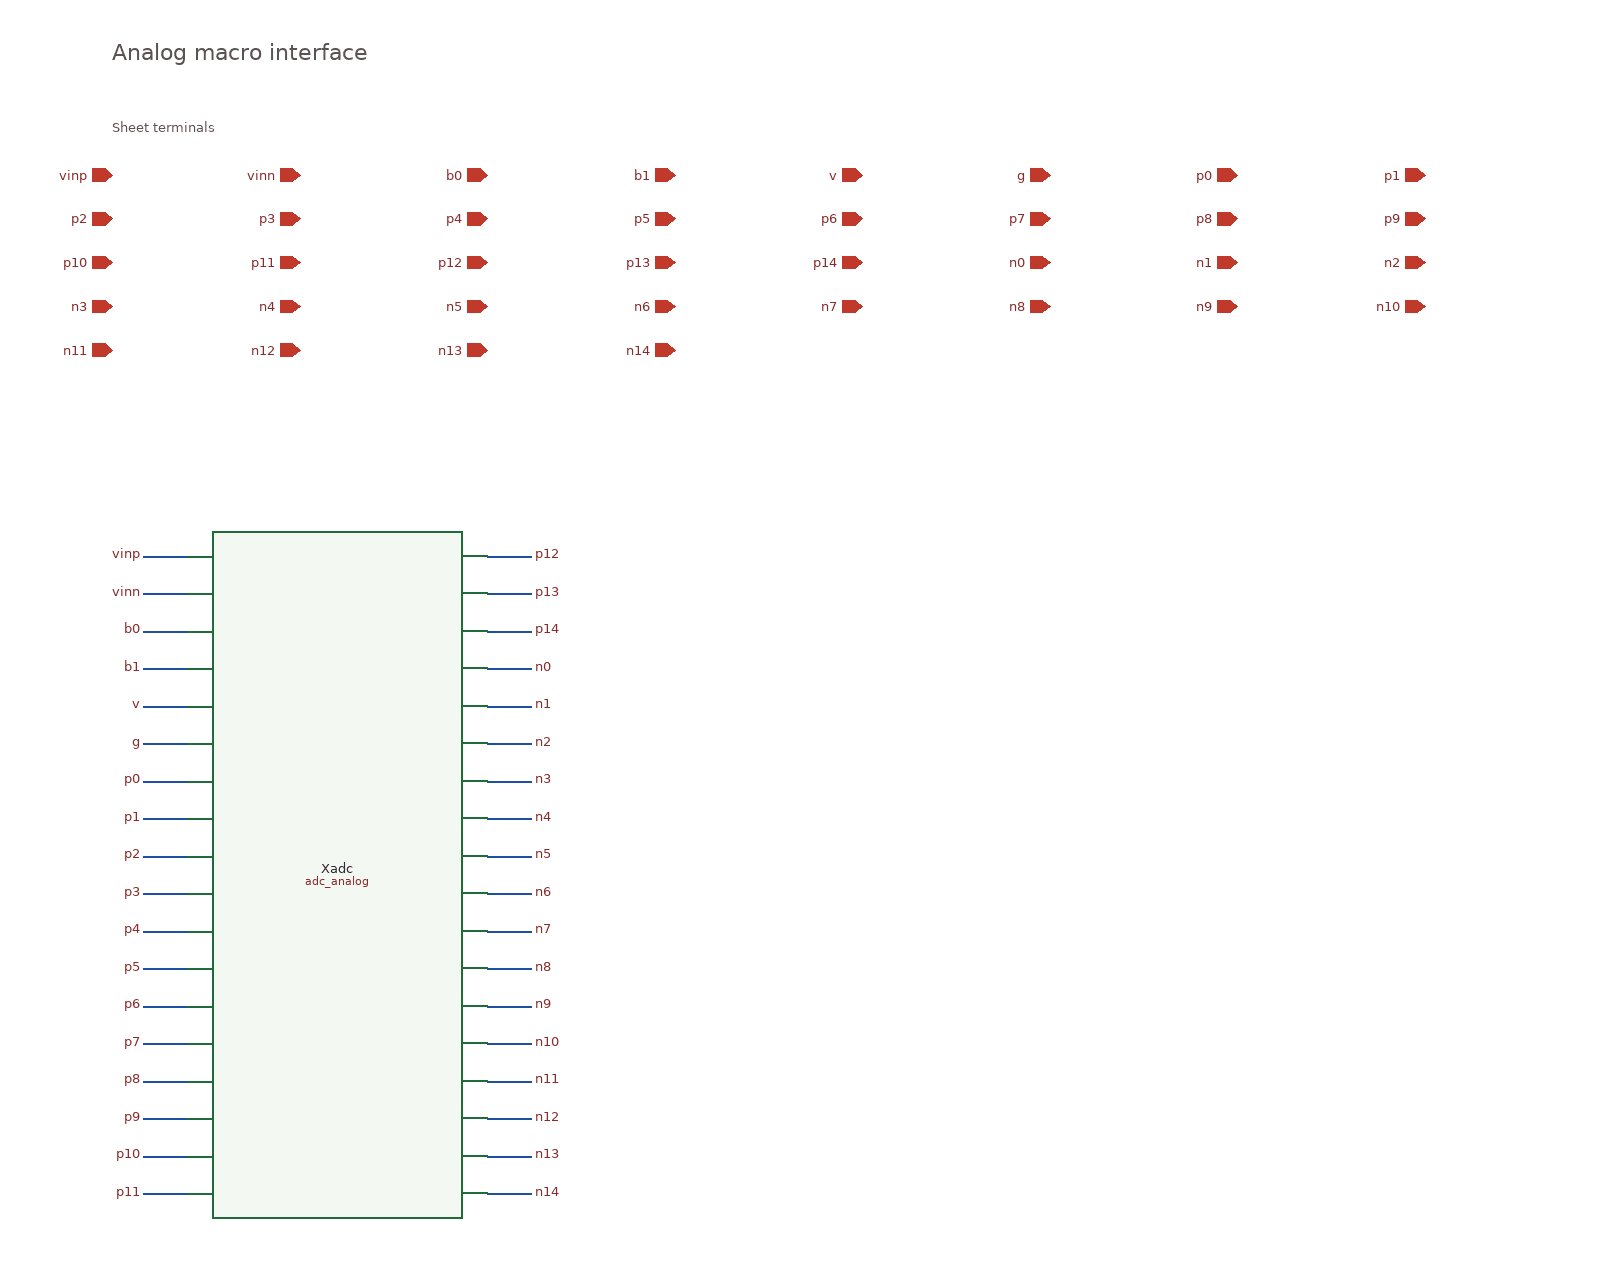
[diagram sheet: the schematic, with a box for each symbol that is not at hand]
v {xschem version=3.4.4 file_version=1.2}
G {}
K {}
V {}
S {}
E {}
T {Analog macro interface} 0 0 0 0 0.62 0.62 {}
T {Sheet terminals} 0 60 0 0 0.32 0.32 {layer=13}
C {devices/iopin.sym} 0 110 0 0 {name=io0 lab=vinp sim_pinnumber=1}
C {devices/iopin.sym} 150 110 0 0 {name=io1 lab=vinn sim_pinnumber=2}
C {devices/iopin.sym} 300 110 0 0 {name=io2 lab=b0 sim_pinnumber=3}
C {devices/iopin.sym} 450 110 0 0 {name=io3 lab=b1 sim_pinnumber=4}
C {devices/iopin.sym} 600 110 0 0 {name=io4 lab=v sim_pinnumber=5}
C {devices/iopin.sym} 750 110 0 0 {name=io5 lab=g sim_pinnumber=6}
C {devices/iopin.sym} 900 110 0 0 {name=io6 lab=p0 sim_pinnumber=7}
C {devices/iopin.sym} 1050 110 0 0 {name=io7 lab=p1 sim_pinnumber=8}
C {devices/iopin.sym} 0 145 0 0 {name=io8 lab=p2 sim_pinnumber=9}
C {devices/iopin.sym} 150 145 0 0 {name=io9 lab=p3 sim_pinnumber=10}
C {devices/iopin.sym} 300 145 0 0 {name=io10 lab=p4 sim_pinnumber=11}
C {devices/iopin.sym} 450 145 0 0 {name=io11 lab=p5 sim_pinnumber=12}
C {devices/iopin.sym} 600 145 0 0 {name=io12 lab=p6 sim_pinnumber=13}
C {devices/iopin.sym} 750 145 0 0 {name=io13 lab=p7 sim_pinnumber=14}
C {devices/iopin.sym} 900 145 0 0 {name=io14 lab=p8 sim_pinnumber=15}
C {devices/iopin.sym} 1050 145 0 0 {name=io15 lab=p9 sim_pinnumber=16}
C {devices/iopin.sym} 0 180 0 0 {name=io16 lab=p10 sim_pinnumber=17}
C {devices/iopin.sym} 150 180 0 0 {name=io17 lab=p11 sim_pinnumber=18}
C {devices/iopin.sym} 300 180 0 0 {name=io18 lab=p12 sim_pinnumber=19}
C {devices/iopin.sym} 450 180 0 0 {name=io19 lab=p13 sim_pinnumber=20}
C {devices/iopin.sym} 600 180 0 0 {name=io20 lab=p14 sim_pinnumber=21}
C {devices/iopin.sym} 750 180 0 0 {name=io21 lab=n0 sim_pinnumber=22}
C {devices/iopin.sym} 900 180 0 0 {name=io22 lab=n1 sim_pinnumber=23}
C {devices/iopin.sym} 1050 180 0 0 {name=io23 lab=n2 sim_pinnumber=24}
C {devices/iopin.sym} 0 215 0 0 {name=io24 lab=n3 sim_pinnumber=25}
C {devices/iopin.sym} 150 215 0 0 {name=io25 lab=n4 sim_pinnumber=26}
C {devices/iopin.sym} 300 215 0 0 {name=io26 lab=n5 sim_pinnumber=27}
C {devices/iopin.sym} 450 215 0 0 {name=io27 lab=n6 sim_pinnumber=28}
C {devices/iopin.sym} 600 215 0 0 {name=io28 lab=n7 sim_pinnumber=29}
C {devices/iopin.sym} 750 215 0 0 {name=io29 lab=n8 sim_pinnumber=30}
C {devices/iopin.sym} 900 215 0 0 {name=io30 lab=n9 sim_pinnumber=31}
C {devices/iopin.sym} 1050 215 0 0 {name=io31 lab=n10 sim_pinnumber=32}
C {devices/iopin.sym} 0 250 0 0 {name=io32 lab=n11 sim_pinnumber=33}
C {devices/iopin.sym} 150 250 0 0 {name=io33 lab=n12 sim_pinnumber=34}
C {devices/iopin.sym} 300 250 0 0 {name=io34 lab=n13 sim_pinnumber=35}
C {devices/iopin.sym} 450 250 0 0 {name=io35 lab=n14 sim_pinnumber=36}
C {adc_analog.sym} 180 415 0 0 {name=Xadc}
N 25 415 60 415 {lab=vinp}
C {devices/lab_pin.sym} 25 415 0 0 {name=net0 lab=vinp}
N 25 445 60 445 {lab=vinn}
C {devices/lab_pin.sym} 25 445 0 0 {name=net1 lab=vinn}
N 25 475 60 475 {lab=b0}
C {devices/lab_pin.sym} 25 475 0 0 {name=net2 lab=b0}
N 25 505 60 505 {lab=b1}
C {devices/lab_pin.sym} 25 505 0 0 {name=net3 lab=b1}
N 25 535 60 535 {lab=v}
C {devices/lab_pin.sym} 25 535 0 0 {name=net4 lab=v}
N 25 565 60 565 {lab=g}
C {devices/lab_pin.sym} 25 565 0 0 {name=net5 lab=g}
N 25 595 60 595 {lab=p0}
C {devices/lab_pin.sym} 25 595 0 0 {name=net6 lab=p0}
N 25 625 60 625 {lab=p1}
C {devices/lab_pin.sym} 25 625 0 0 {name=net7 lab=p1}
N 25 655 60 655 {lab=p2}
C {devices/lab_pin.sym} 25 655 0 0 {name=net8 lab=p2}
N 25 685 60 685 {lab=p3}
C {devices/lab_pin.sym} 25 685 0 0 {name=net9 lab=p3}
N 25 715 60 715 {lab=p4}
C {devices/lab_pin.sym} 25 715 0 0 {name=net10 lab=p4}
N 25 745 60 745 {lab=p5}
C {devices/lab_pin.sym} 25 745 0 0 {name=net11 lab=p5}
N 25 775 60 775 {lab=p6}
C {devices/lab_pin.sym} 25 775 0 0 {name=net12 lab=p6}
N 25 805 60 805 {lab=p7}
C {devices/lab_pin.sym} 25 805 0 0 {name=net13 lab=p7}
N 25 835 60 835 {lab=p8}
C {devices/lab_pin.sym} 25 835 0 0 {name=net14 lab=p8}
N 25 865 60 865 {lab=p9}
C {devices/lab_pin.sym} 25 865 0 0 {name=net15 lab=p9}
N 25 895 60 895 {lab=p10}
C {devices/lab_pin.sym} 25 895 0 0 {name=net16 lab=p10}
N 25 925 60 925 {lab=p11}
C {devices/lab_pin.sym} 25 925 0 0 {name=net17 lab=p11}
N 300 415 335 415 {lab=p12}
C {devices/lab_pin.sym} 335 415 0 1 {name=net18 lab=p12}
N 300 445 335 445 {lab=p13}
C {devices/lab_pin.sym} 335 445 0 1 {name=net19 lab=p13}
N 300 475 335 475 {lab=p14}
C {devices/lab_pin.sym} 335 475 0 1 {name=net20 lab=p14}
N 300 505 335 505 {lab=n0}
C {devices/lab_pin.sym} 335 505 0 1 {name=net21 lab=n0}
N 300 535 335 535 {lab=n1}
C {devices/lab_pin.sym} 335 535 0 1 {name=net22 lab=n1}
N 300 565 335 565 {lab=n2}
C {devices/lab_pin.sym} 335 565 0 1 {name=net23 lab=n2}
N 300 595 335 595 {lab=n3}
C {devices/lab_pin.sym} 335 595 0 1 {name=net24 lab=n3}
N 300 625 335 625 {lab=n4}
C {devices/lab_pin.sym} 335 625 0 1 {name=net25 lab=n4}
N 300 655 335 655 {lab=n5}
C {devices/lab_pin.sym} 335 655 0 1 {name=net26 lab=n5}
N 300 685 335 685 {lab=n6}
C {devices/lab_pin.sym} 335 685 0 1 {name=net27 lab=n6}
N 300 715 335 715 {lab=n7}
C {devices/lab_pin.sym} 335 715 0 1 {name=net28 lab=n7}
N 300 745 335 745 {lab=n8}
C {devices/lab_pin.sym} 335 745 0 1 {name=net29 lab=n8}
N 300 775 335 775 {lab=n9}
C {devices/lab_pin.sym} 335 775 0 1 {name=net30 lab=n9}
N 300 805 335 805 {lab=n10}
C {devices/lab_pin.sym} 335 805 0 1 {name=net31 lab=n10}
N 300 835 335 835 {lab=n11}
C {devices/lab_pin.sym} 335 835 0 1 {name=net32 lab=n11}
N 300 865 335 865 {lab=n12}
C {devices/lab_pin.sym} 335 865 0 1 {name=net33 lab=n12}
N 300 895 335 895 {lab=n13}
C {devices/lab_pin.sym} 335 895 0 1 {name=net34 lab=n13}
N 300 925 335 925 {lab=n14}
C {devices/lab_pin.sym} 335 925 0 1 {name=net35 lab=n14}
